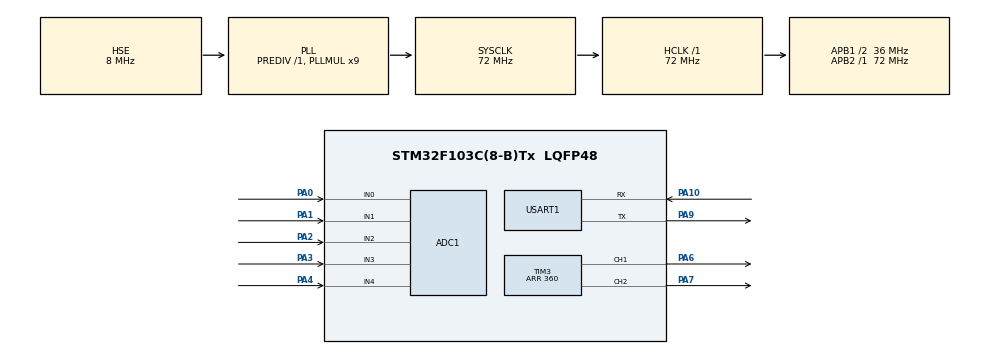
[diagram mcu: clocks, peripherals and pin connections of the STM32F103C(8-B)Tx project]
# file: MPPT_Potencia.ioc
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ADC1.Channel-0\#ChannelRegularConversion=ADC_CHANNEL_0
ADC1.Channel-1\#ChannelRegularConversion=ADC_CHANNEL_1
ADC1.Channel-2\#ChannelRegularConversion=ADC_CHANNEL_2
ADC1.Channel-3\#ChannelRegularConversion=ADC_CHANNEL_3
ADC1.Channel-5\#ChannelRegularConversion=ADC_CHANNEL_4
ADC1.NbrOfConversion=5
ADC1.NbrOfConversionFlag=1
ADC1.Rank-0\#ChannelRegularConversion=1
ADC1.Rank-1\#ChannelRegularConversion=2
ADC1.Rank-2\#ChannelRegularConversion=3
ADC1.Rank-3\#ChannelRegularConversion=4
ADC1.Rank-5\#ChannelRegularConversion=5
ADC1.SamplingTime-0\#ChannelRegularConversion=ADC_SAMPLETIME_13CYCLES_5
ADC1.SamplingTime-1\#ChannelRegularConversion=ADC_SAMPLETIME_13CYCLES_5
ADC1.SamplingTime-2\#ChannelRegularConversion=ADC_SAMPLETIME_13CYCLES_5
ADC1.SamplingTime-3\#ChannelRegularConversion=ADC_SAMPLETIME_13CYCLES_5
ADC1.SamplingTime-5\#ChannelRegularConversion=ADC_SAMPLETIME_13CYCLES_5
ADC1.master=1
Mcu.Family=STM32F1
Mcu.Name=STM32F103C(8-B)Tx
Mcu.Package=LQFP48
NVIC.PriorityGroup=NVIC_PRIORITYGROUP_4
PA0-WKUP.Signal=ADCx_IN0
PA1.Signal=ADCx_IN1
PA10.Mode=Asynchronous
PA10.Signal=USART1_RX
PA2.Signal=ADCx_IN2
PA3.Signal=ADCx_IN3
PA4.Signal=ADCx_IN4
PA6.Signal=S_TIM3_CH1
PA7.Signal=S_TIM3_CH2
PA9.Mode=Asynchronous
PA9.Signal=USART1_TX
PD0-OSC_IN.Mode=HSE-External-Oscillator
PD0-OSC_IN.Signal=RCC_OSC_IN
PD1-OSC_OUT.Mode=HSE-External-Oscillator
PD1-OSC_OUT.Signal=RCC_OSC_OUT
ProjectManager.HeapSize=0x200
ProjectManager.StackSize=0x400
ProjectManager.TargetToolchain=STM32CubeIDE
RCC.ADCPresc=RCC_ADCPCLK2_DIV6
RCC.AHBFreq_Value=72000000
RCC.APB1CLKDivider=RCC_HCLK_DIV2
RCC.APB1Freq_Value=36000000
RCC.APB1TimFreq_Value=72000000
RCC.APB2Freq_Value=72000000
RCC.APB2TimFreq_Value=72000000
RCC.HCLKFreq_Value=72000000
RCC.PLLMUL=RCC_PLL_MUL9
RCC.PLLSourceVirtual=RCC_PLLSOURCE_HSE
RCC.SYSCLKFreq_VALUE=72000000
RCC.SYSCLKSource=RCC_SYSCLKSOURCE_PLLCLK
RCC.USBFreq_Value=72000000
SH.ADCx_IN0.0=ADC1_IN0,IN0
SH.ADCx_IN1.0=ADC1_IN1,IN1
SH.ADCx_IN2.0=ADC1_IN2,IN2
SH.ADCx_IN3.0=ADC1_IN3,IN3
SH.ADCx_IN4.0=ADC1_IN4,IN4
SH.S_TIM3_CH1.0=TIM3_CH1,PWM Generation1 CH1
SH.S_TIM3_CH2.0=TIM3_CH2,PWM Generation2 CH2
TIM3.AutoReloadPreload=TIM_AUTORELOAD_PRELOAD_ENABLE
TIM3.Channel-PWM\ Generation1\ CH1=TIM_CHANNEL_1
TIM3.Channel-PWM\ Generation2\ CH2=TIM_CHANNEL_2
TIM3.Period=360
TIM3.Pulse-PWM\ Generation1\ CH1=150
USART1.VirtualMode=VM_ASYNC
VP_TIM3_VS_ClockSourceINT.Mode=Internal
board=custom

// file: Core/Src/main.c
/* USER CODE BEGIN Header */
/**
  ******************************************************************************
  * @file           : main.c
  * @brief          : Main program body
  ******************************************************************************
  * @attention
  *
  * Copyright (c) 2023 STMicroelectronics.
  * All rights reserved.
  *
  * This software is licensed under terms that can be found in the LICENSE file
  * in the root directory of this software component.
  * If no LICENSE file comes with this software, it is provided AS-IS.
  *
  ******************************************************************************
  */
/* USER CODE END Header */
#include "main.h"

/* USER CODE BEGIN PD */

#define DEBUG_MODE 3
#define DUTY1 	180
#define	DUTY2   250

#define L_PERIOD 50 //Titilar 1 segundo
/* USER CODE END PD */

//ADC_HandleTypeDef hadc1;

TIM_HandleTypeDef htim3;

UART_HandleTypeDef huart1;

/* USER CODE BEGIN PV */

uint8_t flag_led=1;

/* USER CODE END PV */

void SystemClock_Config(void);
static void MX_GPIO_Init(void);
static void MX_TIM3_Init(void);
//static void MX_ADC1_Init(void);
static void MX_USART1_UART_Init(void);
/* USER CODE BEGIN PFP */
void T_Led_Out(void);
/* USER CODE END PFP */

/* USER CODE BEGIN 0 */
void T_Led_Out(void){
  flag_led=1;
}
/* USER CODE END 0 */

int main(void)
{

  /* MCU Configuration--------------------------------------------------------*/

  /* Reset of all peripherals, Initializes the Flash interface and the Systick. */
  HAL_Init();

  /* Configure the system clock */
  SystemClock_Config();

  /* Initialize all configured peripherals */
  MX_GPIO_Init();
  MX_TIM3_Init();
  MX_ADC1_Init();
  MX_USART1_UART_Init();
  /* USER CODE BEGIN 2 */
  HAL_TIM_PWM_Start(&htim3, TIM_CHANNEL_1);
  HAL_TIM_PWM_Start(&htim3, TIM_CHANNEL_2);
  BUCK_init ();
//  HAL_GPIO_WritePin(GPIOB, GPIO_PIN_1, GPIO_PIN_SET);
  /* USER CODE END 2 */

  /* Infinite loop */
  /* USER CODE BEGIN WHILE */
  while (1){
	  if (DEBUG_MODE == 1){
		  if (flag_led == 1){
			  debug_function_1();
			  flag_led = 0;
			  TimerStart(1,L_PERIOD,&T_Led_Out);
      }
    }
	  else if (DEBUG_MODE == 2){
		  if (flag_led == 1){
        debug_function_2();
			  flag_led = 0;
			  TimerStart(1,L_PERIOD,&T_Led_Out);
		  }
    }
    else if (DEBUG_MODE == 3){
      if (flag_led == 1){
        debug_function_3();
        flag_led=0;
        TimerStart(1,L_PERIOD,&T_Led_Out);
        HAL_GPIO_TogglePin(GPIOB, GPIO_PIN_0);
      }
    }
    else{
      Mde_MPPT_Out();
    }
    TimerEvent();
  }
    /* USER CODE END WHILE */

}

void SystemClock_Config(void)
{
  RCC_OscInitTypeDef RCC_OscInitStruct = {0};
  RCC_ClkInitTypeDef RCC_ClkInitStruct = {0};
  RCC_PeriphCLKInitTypeDef PeriphClkInit = {0};

  /** Initializes the RCC Oscillators according to the specified parameters
  * in the RCC_OscInitTypeDef structure.
  */
  RCC_OscInitStruct.OscillatorType = RCC_OSCILLATORTYPE_HSE;
  RCC_OscInitStruct.HSEState = RCC_HSE_ON;
  RCC_OscInitStruct.HSEPredivValue = RCC_HSE_PREDIV_DIV1;
  RCC_OscInitStruct.HSIState = RCC_HSI_ON;
  RCC_OscInitStruct.PLL.PLLState = RCC_PLL_ON;
  RCC_OscInitStruct.PLL.PLLSource = RCC_PLLSOURCE_HSE;
  RCC_OscInitStruct.PLL.PLLMUL = RCC_PLL_MUL9;
  if (HAL_RCC_OscConfig(&RCC_OscInitStruct) != HAL_OK)
  {
    Error_Handler();
  }

  /** Initializes the CPU, AHB and APB buses clocks
  */
  RCC_ClkInitStruct.ClockType = RCC_CLOCKTYPE_HCLK|RCC_CLOCKTYPE_SYSCLK
                              |RCC_CLOCKTYPE_PCLK1|RCC_CLOCKTYPE_PCLK2;
  RCC_ClkInitStruct.SYSCLKSource = RCC_SYSCLKSOURCE_PLLCLK;
  RCC_ClkInitStruct.AHBCLKDivider = RCC_SYSCLK_DIV1;
  RCC_ClkInitStruct.APB1CLKDivider = RCC_HCLK_DIV2;
  RCC_ClkInitStruct.APB2CLKDivider = RCC_HCLK_DIV1;

  if (HAL_RCC_ClockConfig(&RCC_ClkInitStruct, FLASH_LATENCY_2) != HAL_OK)
  {
    Error_Handler();
  }
  PeriphClkInit.PeriphClockSelection = RCC_PERIPHCLK_ADC;
  PeriphClkInit.AdcClockSelection = RCC_ADCPCLK2_DIV6;
  if (HAL_RCCEx_PeriphCLKConfig(&PeriphClkInit) != HAL_OK)
  {
    Error_Handler();
  }
}

// static void MX_ADC1_Init(void)
// {

//   /* USER CODE BEGIN ADC1_Init 0 */

//   /* USER CODE END ADC1_Init 0 */

//   ADC_ChannelConfTypeDef sConfig = {0};

//   /* USER CODE BEGIN ADC1_Init 1 */

//   /* USER CODE END ADC1_Init 1 */

//   /** Common config
//   */
//   hadc1.Instance = ADC1;
//   hadc1.Init.ScanConvMode = ADC_SCAN_ENABLE;
//   hadc1.Init.ContinuousConvMode = DISABLE;
//   hadc1.Init.DiscontinuousConvMode = DISABLE;
//   hadc1.Init.ExternalTrigConv = ADC_SOFTWARE_START;
//   hadc1.Init.DataAlign = ADC_DATAALIGN_RIGHT;
//   hadc1.Init.NbrOfConversion = 5;
//   if (HAL_ADC_Init(&hadc1) != HAL_OK)
//   {
//     Error_Handler();
//   }

//   /** Configure Regular Channel
//   */
//   sConfig.Channel = ADC_CHANNEL_0;
//   sConfig.Rank = ADC_REGULAR_RANK_1;
//   sConfig.SamplingTime = ADC_SAMPLETIME_13CYCLES_5;
//   if (HAL_ADC_ConfigChannel(&hadc1, &sConfig) != HAL_OK)
//   {
//     Error_Handler();
//   }

//   /** Configure Regular Channel
//   */
//   sConfig.Channel = ADC_CHANNEL_1;
//   sConfig.Rank = ADC_REGULAR_RANK_2;
//   if (HAL_ADC_ConfigChannel(&hadc1, &sConfig) != HAL_OK)
//   {
//     Error_Handler();
//   }

//   /** Configure Regular Channel
//   */
//   sConfig.Channel = ADC_CHANNEL_2;
//   sConfig.Rank = ADC_REGULAR_RANK_3;
//   if (HAL_ADC_ConfigChannel(&hadc1, &sConfig) != HAL_OK)
//   {
//     Error_Handler();
//   }

//   /** Configure Regular Channel
//   */
//   sConfig.Channel = ADC_CHANNEL_3;
//   sConfig.Rank = ADC_REGULAR_RANK_4;
//   if (HAL_ADC_ConfigChannel(&hadc1, &sConfig) != HAL_OK)
//   {
//     Error_Handler();
//   }

//   /** Configure Regular Channel
//   */
//   sConfig.Channel = ADC_CHANNEL_4;
//   sConfig.Rank = ADC_REGULAR_RANK_5;
//   if (HAL_ADC_ConfigChannel(&hadc1, &sConfig) != HAL_OK)
//   {
//     Error_Handler();
//   }
//   /* USER CODE BEGIN ADC1_Init 2 */

//   /* USER CODE END ADC1_Init 2 */

// }

// /**
//   * @brief TIM3 Initialization Function
//   * @param None
//   * @retval None
//   */
static void MX_TIM3_Init(void)
{

  TIM_ClockConfigTypeDef sClockSourceConfig = {0};
  TIM_MasterConfigTypeDef sMasterConfig = {0};
  TIM_OC_InitTypeDef sConfigOC = {0};

  htim3.Instance = TIM3;
  htim3.Init.Prescaler = 0;
  htim3.Init.CounterMode = TIM_COUNTERMODE_UP;
  htim3.Init.Period = 360;
  htim3.Init.ClockDivision = TIM_CLOCKDIVISION_DIV1;
  htim3.Init.AutoReloadPreload = TIM_AUTORELOAD_PRELOAD_ENABLE;
  if (HAL_TIM_Base_Init(&htim3) != HAL_OK)
  {
    Error_Handler();
  }
  sClockSourceConfig.ClockSource = TIM_CLOCKSOURCE_INTERNAL;
  if (HAL_TIM_ConfigClockSource(&htim3, &sClockSourceConfig) != HAL_OK)
  {
    Error_Handler();
  }
  if (HAL_TIM_PWM_Init(&htim3) != HAL_OK)
  {
    Error_Handler();
  }
  sMasterConfig.MasterOutputTrigger = TIM_TRGO_RESET;
  sMasterConfig.MasterSlaveMode = TIM_MASTERSLAVEMODE_DISABLE;
  if (HAL_TIMEx_MasterConfigSynchronization(&htim3, &sMasterConfig) != HAL_OK)
  {
    Error_Handler();
  }
  sConfigOC.OCMode = TIM_OCMODE_PWM1;
  sConfigOC.Pulse = 150;
  sConfigOC.OCPolarity = TIM_OCPOLARITY_HIGH;
  sConfigOC.OCFastMode = TIM_OCFAST_DISABLE;
  if (HAL_TIM_PWM_ConfigChannel(&htim3, &sConfigOC, TIM_CHANNEL_1) != HAL_OK)
  {
    Error_Handler();
  }
  sConfigOC.Pulse = 0;
  if (HAL_TIM_PWM_ConfigChannel(&htim3, &sConfigOC, TIM_CHANNEL_2) != HAL_OK)
  {
    Error_Handler();
  }
  HAL_TIM_MspPostInit(&htim3);

}

static void MX_USART1_UART_Init(void)
{

  huart1.Instance = USART1;
  huart1.Init.BaudRate = 115200;
  huart1.Init.WordLength = UART_WORDLENGTH_8B;
  huart1.Init.StopBits = UART_STOPBITS_1;
  huart1.Init.Parity = UART_PARITY_NONE;
  huart1.Init.Mode = UART_MODE_TX_RX;
  huart1.Init.HwFlowCtl = UART_HWCONTROL_NONE;
  huart1.Init.OverSampling = UART_OVERSAMPLING_16;
  if (HAL_UART_Init(&huart1) != HAL_OK)
  {
    Error_Handler();
  }

}

static void MX_GPIO_Init(void)
{
  GPIO_InitTypeDef GPIO_InitStruct = {0};

  /* GPIO Ports Clock Enable */
  __HAL_RCC_GPIOD_CLK_ENABLE();
  __HAL_RCC_GPIOA_CLK_ENABLE();
  __HAL_RCC_GPIOB_CLK_ENABLE();

    /*Configure GPIO pin Output Level */
  HAL_GPIO_WritePin(GPIOB, GPIO_PIN_0|GPIO_PIN_1, GPIO_PIN_RESET);

  /*Configure GPIO pins : PB0 PB1 */
  GPIO_InitStruct.Pin = GPIO_PIN_0|GPIO_PIN_1;
  GPIO_InitStruct.Mode = GPIO_MODE_OUTPUT_PP;
  GPIO_InitStruct.Pull = GPIO_NOPULL;
  GPIO_InitStruct.Speed = GPIO_SPEED_FREQ_LOW;
  HAL_GPIO_Init(GPIOB, &GPIO_InitStruct);

}

void Error_Handler(void)
{
  __disable_irq();
  while (1)
  {
  }
}
